VERSION 5.8 ;
BUSBITCHARS "[]" ;
DIVIDERCHAR "/" ;
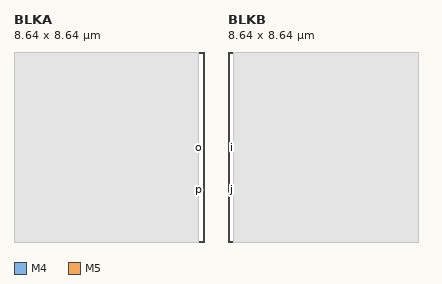
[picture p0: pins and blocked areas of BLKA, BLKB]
MACRO BLKA
  CLASS BLOCK ;
  ORIGIN 0 0 ;
  SIZE 8.64 BY 8.64 ;
  PIN o
    DIRECTION OUTPUT ;
    USE SIGNAL ;
    PORT
      LAYER M4 ;
        RECT 8.448 4.296 8.64 4.344 ;
    END
  END o
  PIN p
    DIRECTION OUTPUT ;
    USE SIGNAL ;
    PORT
      LAYER M4 ;
        RECT 8.448 2.376 8.64 2.424 ;
    END
  END p
  OBS
    LAYER M1 ;
      RECT 0 0 8.4 8.64 ;
  END
END BLKA
MACRO BLKB
  CLASS BLOCK ;
  ORIGIN 0 0 ;
  SIZE 8.64 BY 8.64 ;
  PIN i
    DIRECTION INPUT ;
    USE SIGNAL ;
    PORT
      LAYER M5 ;
        RECT 0 4.296 0.192 4.344 ;
    END
  END i
  PIN j
    DIRECTION INPUT ;
    USE SIGNAL ;
    PORT
      LAYER M4 ;
        RECT 0 2.376 0.192 2.424 ;
    END
  END j
  OBS
    LAYER M1 ;
      RECT 0.24 0 8.64 8.64 ;
  END
END BLKB
END LIBRARY
